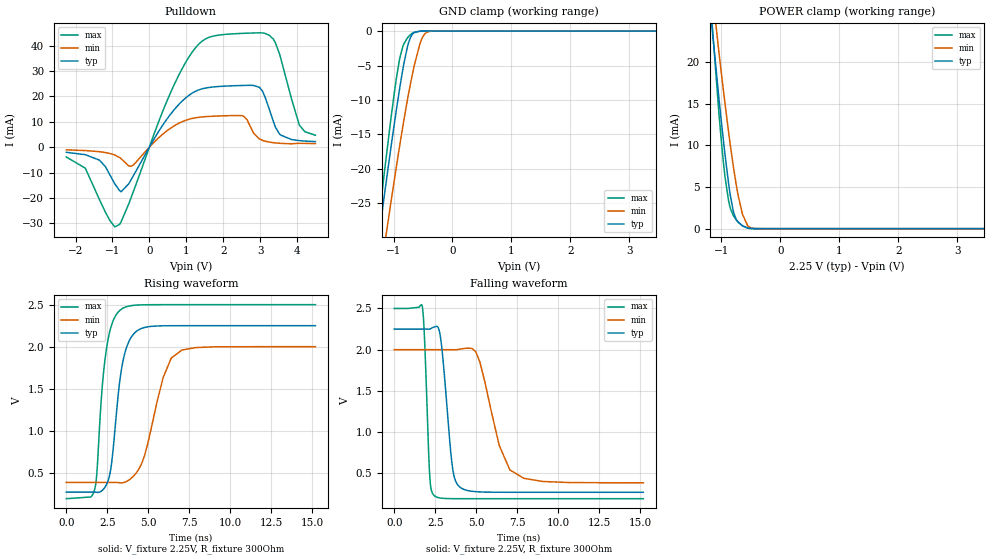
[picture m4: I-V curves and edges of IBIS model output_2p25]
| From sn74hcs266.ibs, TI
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|   output_2p25 Model
[Model]   output_2p25
Model_type   Output
Polarity   Non-Inverting
Vmeas = 1.125
Vref = 0
Cref = 2pF
Rref = 100000
|   typ   min   max
C_comp   0.937pF   0.886pF   0.963pF
| Where Nom  PVT is Nominal Process, 2.25V, 27C
|   Fast PVT is Strong Process,  2.50V, -55C
|   Slow PVT is Weak Process,   2.0V, 150C
[Voltage Range]   2.25   2   2.5
|Junction Temperature
[Temperature Range]   27   150   -55
[Pulldown Reference]   0   0   0
[Power Clamp Reference]   2.25   2   2.5
[GND Clamp Reference]   0   0   0
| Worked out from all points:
|   slope of the pulldown table from 0 to 0.337 V, typ, clamps not added: 41.6 ohm
|   GND clamp passes 1 mA (typ) near -0.72 V on its own axis
|   POWER clamp passes 1 mA (typ) near -0.74 V on its own axis
|   falling waveform, V_fixture 2.25V, R_fixture 300Ohm: 20-80 % time 508ps typ, 1.25ns min, 251ps max; typ from 2.25 V to 0.269 V
|   rising waveform, V_fixture 2.25V, R_fixture 300Ohm: 20-80 % time 690ps typ, 1.22ns min, 587ps max; typ from 0.269 V to 2.25 V
[Pulldown]
|   Voltage   I(typ)   I(min)   I(max)
-2.25V    -2.019mA   -1.051mA   -3.867mA
-1.737V   -2.956mA   -1.338mA   -8.261mA
-1.352V   -5.109mA   -1.777mA   -20.65mA
-805.5mV  -17.13mA   -4.093mA   -30.48mA
-461.2mV  -11.99mA   -7.313mA   -18.63mA
949.5mV   18.99mA    10.42mA    32.57mA
2.057V    24.09mA    12.39mA    44.49mA
2.556V    24.35mA    12.19mA    44.91mA
2.981V    23.61mA    3.258mA    45.1mA
3.359V    10.14mA    1.771mA    42.63mA
4.061V    2.596mA    1.53mA     8.818mA
4.5V      2.197mA    1.398mA    4.702mA
[GND Clamp]
|   Voltage   I(typ)   I(min)   I(max)
-2.25V    -97.51mA   -98.31mA   -106.7mA
-1.413V   -40.56mA   -46.57mA   -39.9mA
-1.17V    -24.74mA   -32.11mA   -21.56mA
-1.157V   -23.88mA   -31.32mA   -20.58mA
-1.048V   -17.16mA   -25.09mA   -13.01mA
-954mV    -11.56mA   -19.8mA    -7.02mA
-886.5mV  -7.821mA   -16.15mA   -3.647mA
-758.2mV  -2.094mA   -9.706mA   -933.8uA
-650.2mV  -236.3uA   -5.079mA   -178.5uA
-515.2mV  -9.553uA   -1.047mA   -5.579uA
-373.5mV  -159.7nA   -38.68uA   -18.72nA
4.5V      0A         0A         0A
[POWER Clamp]
|   Voltage   I(typ)   I(min)   I(max)
-2.25V    111.3mA    101.8mA    143.6mA
-1.305V   34.66mA    37.92mA    38.3mA
-1.042V   15.57mA    21.11mA    13.76mA
-987.8mV  11.94mA    17.84mA    9.441mA
-940.5mV  8.946mA    15.06mA    6.255mA
-879.8mV  5.467mA    11.64mA    3.383mA
-792mV    1.914mA    7.17mA     1.486mA
-717.7mV  771.2uA    4.03mA     811.5uA
-643.5mV  332.5uA    1.729mA    341.9uA
-555.7mV  82.38uA    359.8uA    63.02uA
-420.8mV  3.273uA    16.09uA    933.6nA
4.5V      0A         0A         0A
[Ramp]
R_load = 300
|   typ   min   max
dV/dt_r   1.35/810e-12   1.2/1.923e-9   1.5/613e-12
dV/dt_f   1.35/656e-12   1.2/2.74e-9   1.5/301.4e-12
[Falling Waveform]
V_fixture = 2.25V
V_fixture_min = 2V
V_fixture_max = 2.5V
R_fixture = 300Ohm
C_fixture = 0F
|   Time   V(typ)   V(min)   V(max)
0s        2.25V      2V         2.5V
1.706ns   2.25V      2V         2.531V
2.161ns   2.25V      2V         482.9mV
2.438ns   2.276V     2V         229mV
2.826ns   2.144V     2V         198.9mV
3.514ns   631.3mV    2V         191.9mV
3.978ns   335.9mV    2.005V     191.5mV
4.976ns   276.4mV    1.973V     191.4mV
7.047ns   269.4mV    542mV      191.4mV
15.19ns   269.3mV    384.5mV    191.4mV
[Rising Waveform]
V_fixture = 2.25V
V_fixture_min = 2V
V_fixture_max = 2.5V
R_fixture = 300Ohm
C_fixture = 0F
|   Time   V(typ)   V(min)   V(max)
0s        269.3mV    384.5mV    191.4mV
1.715ns   269.5mV    384.5mV    291.3mV
2.438ns   353.1mV    384.5mV    1.96V
2.778ns   635.6mV    384.7mV    2.267V
3.278ns   1.616V     380.4mV    2.434V
4.252ns   2.179V     494.7mV    2.494V
4.764ns   2.228V     700.1mV    2.498V
5.907ns   2.248V     1.635V     2.5V
7.047ns   2.25V      1.96V      2.5V
15.19ns   2.25V      2V         2.5V
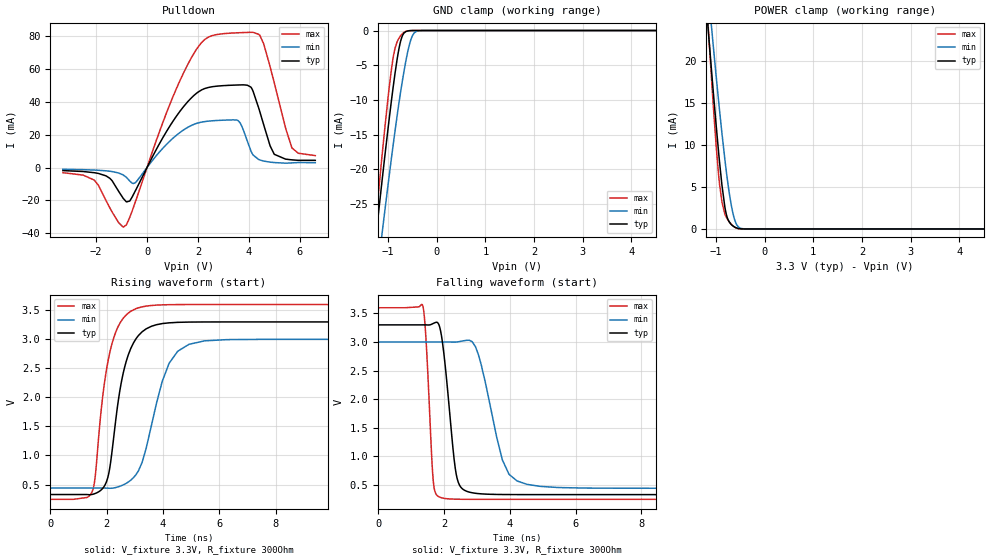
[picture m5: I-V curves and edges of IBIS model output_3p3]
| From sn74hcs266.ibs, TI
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|   output_3p3 Model
[Model]   output_3p3
Model_type   Output
Polarity   Non-Inverting
Vmeas = 1.65
Vref = 0
Cref = 2pF
Rref = 100000
|   typ   min   max
C_comp   0.878pF   0.839pF   0.891pF
| Where Nom  PVT is Nominal Process, 3.3V, 27C
|   Fast PVT is Strong Process,  3.6V, -55C
|   Slow PVT is Weak Process,   3.0V, 150C
[Voltage Range]   3.3   3   3.6
|Junction Temperature
[Temperature Range]   27   150   -55
[Pulldown Reference]   0   0   0
[Power Clamp Reference]   3.3   3   3.6
[GND Clamp Reference]   0   0   0
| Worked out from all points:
|   slope of the pulldown table from 0 to 0.495 V, typ, clamps not added: 33.8 ohm
|   GND clamp passes 1 mA (typ) near -0.72 V on its own axis
|   POWER clamp passes 1 mA (typ) near -0.74 V on its own axis
|   falling waveform, V_fixture 3.3V, R_fixture 300Ohm: 20-80 % time 299ps typ, 590ps min, 168ps max; typ from 3.3 V to 0.328 V
|   rising waveform, V_fixture 3.3V, R_fixture 300Ohm: 20-80 % time 599ps typ, 838ps min, 545ps max; typ from 0.328 V to 3.3 V
[Pulldown]
|   Voltage   I(typ)   I(min)   I(max)
-3.3V     -1.874mA   -1.09mA    -3.153mA
-2.072V   -3.148mA   -1.553mA   -7.616mA
-815.1mV  -20.76mA   -5.906mA   -34.91mA
-468.6mV  -14.47mA   -9.363mA   -21.34mA
1.719V    41.96mA    25.37mA    66.07mA
3.244V    49.91mA    28.86mA    81.54mA
3.66V     50.14mA    26.88mA    81.86mA
4.075V    48.79mA    10.04mA    82.07mA
4.422V    33.99mA    4.608mA    80.33mA
4.986V    8.151mA    3.011mA    51.62mA
5.679V    4.642mA    2.795mA    12.07mA
6.6V      4.33mA     2.888mA    7.224mA
[GND Clamp]
|   Voltage   I(typ)   I(min)   I(max)
-3.3V     -170.7mA   -164.8mA   -192.4mA
-1.27V    -31.2mA    -38.03mA   -29.01mA
-1.122V   -21.71mA   -29.31mA   -18.11mA
-1.073V   -18.63mA   -26.46mA   -14.64mA
-983.4mV  -13.27mA   -21.43mA   -8.78mA
-894.3mV  -8.237mA   -16.57mA   -3.969mA
-815.1mV  -4.303mA   -12.46mA   -1.69mA
-755.7mV  -2.013mA   -9.587mA   -907.2uA
-636.9mV  -174.3uA   -4.574mA   -135.1uA
-498.3mV  -6.151uA   -766.4uA   -3.251uA
-339.9mV  -43.96nA   -15.79uA   0A
6.6V      0A         0A         0A
[POWER Clamp]
|   Voltage   I(typ)   I(min)   I(max)
-3.3V     211.7mA    184.7mA    283.2mA
-1.152V   23.34mA    28mA       23.6mA
-1.073V   17.7mA     23.01mA    16.41mA
-993.3mV  12.31mA    18.17mA    9.859mA
-943.8mV  9.149mA    15.25mA    6.453mA
-874.5mV  5.196mA    11.36mA    3.199mA
-815.1mV  2.61mA     8.282mA    1.781mA
-765.6mV  1.349mA    5.972mA    1.216mA
-666.6mV  440uA      2.342mA    466.4uA
-577.5mV  123.3uA    563.4uA    104.5uA
-290.4mV  398.2nA    738.5nA    0A
6.6V      0A         0A         0A
[Ramp]
R_load = 300
|   typ   min   max
dV/dt_r   1.98/645e-12   1.8/1.04e-9   2.16/559e-12
dV/dt_f   1.98/353e-12   1.8/816e-12   2.16/196.5e-12
[Falling Waveform]
V_fixture = 3.3V
V_fixture_min = 3V
V_fixture_max = 3.6V
R_fixture = 300Ohm
C_fixture = 0F
|   Time   V(typ)   V(min)   V(max)
0s        3.3V       3V         3.6V
1.357ns   3.3V       3V         3.63V
1.672ns   3.325V     3V         576.9mV
1.897ns   3.194V     3V         277mV
2.344ns   783.3mV    2.999V     247.9mV
2.696ns   384.6mV    3.03V      245.5mV
3.048ns   345mV      2.775V     245.1mV
3.774ns   329.4mV    935.7mV    245mV
4.219ns   328mV      567.2mV    245mV
15.48ns   327.5mV    438.8mV    245mV
[Rising Waveform]
V_fixture = 3.3V
V_fixture_min = 3V
V_fixture_max = 3.6V
R_fixture = 300Ohm
C_fixture = 0F
|   Time   V(typ)   V(min)   V(max)
0s        327.5mV    438.8mV    245mV
1.475ns   328.2mV    438.8mV    365.8mV
1.594ns   345.3mV    438.8mV    627.8mV
1.945ns   493.5mV    438.9mV    2.319V
2.114ns   789.2mV    435.4mV    2.772V
2.55ns    2.327V     485.3mV    3.336V
3.048ns   3.013V     672.2mV    3.529V
4.219ns   3.284V     2.587V     3.597V
4.93ns    3.297V     2.915V     3.599V
15.48ns   3.3V       3V         3.6V
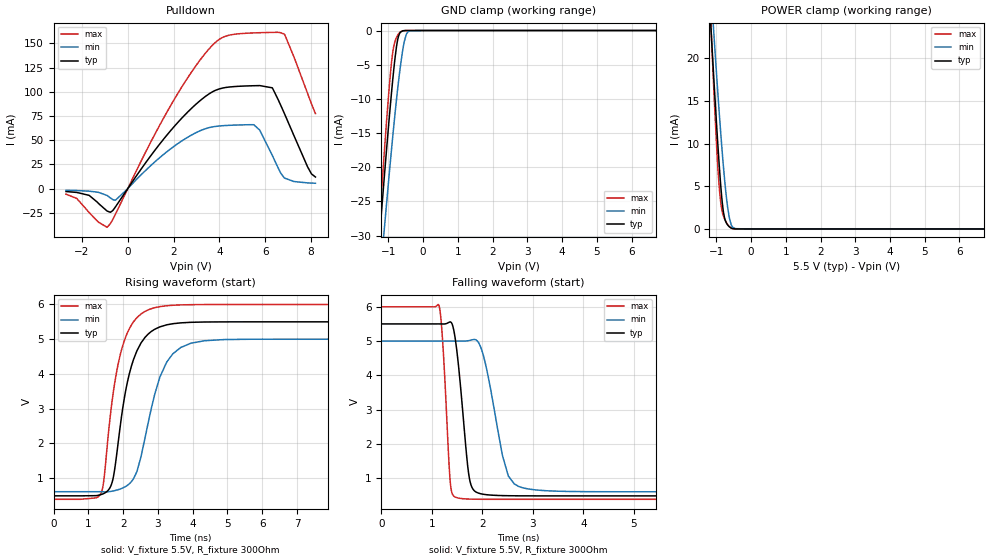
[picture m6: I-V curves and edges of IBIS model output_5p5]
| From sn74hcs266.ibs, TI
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|   output_5p5 Model
[Model]   output_5p5
Model_type   Output
Polarity   Non-Inverting
Vmeas = 2.75
Vref = 0
Cref = 2pF
Rref = 100000
|   typ   min   max
C_comp   0.801pF   0.769pF   0.801pF
| Where Nom  PVT is Nominal Process, 5.5V, 27C
|   Fast PVT is Strong Process,  6.0V, -55C
|   Slow PVT is Weak Process,   5.0V, 150C
[Voltage Range]   5.5   5   6
|Junction Temperature
[Temperature Range]   27   150   -55
[Pulldown Reference]   0   0   0
[Power Clamp Reference]   5.5   5   6
[GND Clamp Reference]   0   0   0
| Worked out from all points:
|   slope of the pulldown table from 0 to 0.825 V, typ, clamps not added: 29.3 ohm
|   GND clamp passes 1 mA (typ) near -0.72 V on its own axis
|   POWER clamp passes 1 mA (typ) near -0.74 V on its own axis
|   falling waveform, V_fixture 5.5V, R_fixture 300Ohm: 20-80 % time 189ps typ, 339ps min, 118ps max; typ from 5.5 V to 0.481 V
|   rising waveform, V_fixture 5.5V, R_fixture 300Ohm: 20-80 % time 540ps typ, 675ps min, 504ps max; typ from 0.481 V to 5.5 V
[Pulldown]
|   Voltage   I(typ)   I(min)   I(max)
-2.7V     -3.055mA   -1.706mA   -5.778mA
-1.686V   -7.04mA    -2.68mA    -24.81mA
-901.5mV  -23.23mA   -7.206mA   -39.81mA
-541.8mV  -18.99mA   -12.08mA   -26.61mA
2.325V    71.94mA    48.73mA    103.7mA
3.546V    97.82mA    62.97mA    144.3mA
4.309V    104.6mA    65.26mA    157.8mA
5.508V    106.3mA    65.99mA    160.9mA
6.314V    104.2mA    34.33mA    161.5mA
6.827V    78.5mA     11.4mA     159.8mA
7.862V    22.23mA    5.883mA    97.97mA
8.2V      11.95mA    5.526mA    77.53mA
[GND Clamp]
|   Voltage   I(typ)   I(min)   I(max)
-2.7V     -128.8mA   -126.7mA   -143.3mA
-1.37V    -37.73mA   -43.99mA   -36.6mA
-1.25V    -29.89mA   -36.83mA   -27.5mA
-1.119V   -21.55mA   -29.17mA   -17.93mA
-988.7mV  -13.58mA   -21.72mA   -9.11mA
-901.5mV  -8.626mA   -16.95mA   -4.285mA
-836.1mV  -5.272mA   -13.52mA   -2.102mA
-759.8mV  -2.144mA   -9.779mA   -950.2uA
-650.8mV  -239.3uA   -5.101mA   -180.5uA
-541.8mV  -18.61uA   -1.605mA   -12.31uA
-378.3mV  -181.5nA   -43.9uA    -26.91nA
8.2V      0A         0A         0A
[POWER Clamp]
|   Voltage   I(typ)   I(min)   I(max)
-2.7V     153.5mA    137.3mA    203.1mA
-1.207V   27.35mA    31.53mA    28.8mA
-1.098V   19.47mA    24.59mA    18.65mA
-1.054V   16.42mA    21.87mA    14.81mA
-966.9mV  10.6mA     16.6mA     7.948mA
-879.7mV  5.467mA    11.64mA    3.382mA
-814.3mV  2.584mA    8.244mA    1.77mA
-759.8mV  1.253mA    5.722mA    1.163mA
-672.6mV  471.3uA    2.518mA    502uA
-574.5mV  116.9uA    531.2uA    97.83uA
-29.5mV   0A         0A         0A
8.2V      0A         0A         0A
[Ramp]
R_load = 300
|   typ   min   max
dV/dt_r   3.3/560e-12   3/729e-12   3.6/513e-12
dV/dt_f   3.3/212.6e-12   3/392e-12   3.6/134e-12
[Falling Waveform]
V_fixture = 5.5V
V_fixture_min = 5V
V_fixture_max = 6V
R_fixture = 300Ohm
C_fixture = 0F
|   Time   V(typ)   V(min)   V(max)
0s        5.5V       5V         6V
1.136ns   5.5V       5V         6.052V
1.216ns   5.498V     5V         4.922V
1.367ns   5.559V     5V         823.6mV
1.52ns    4.37V      5V         418.5mV
1.793ns   730.3mV    5.034V     385.8mV
2.018ns   528.6mV    4.586V     381.7mV
2.514ns   486.1mV    1.06V      380.6mV
2.905ns   482mV      683.9mV    380.5mV
15.46ns   481mV      600.3mV    380.5mV
[Rising Waveform]
V_fixture = 5.5V
V_fixture_min = 5V
V_fixture_max = 6V
R_fixture = 300Ohm
C_fixture = 0F
|   Time   V(typ)   V(min)   V(max)
0s        480.9mV    600.3mV    380.5mV
1.34ns    510.4mV    601mV      516.4mV
1.446ns   548.9mV    597.1mV    928mV
1.615ns   704.1mV    605.1mV    2.641V
2.054ns   3.405V     740.3mV    5.008V
2.396ns   4.662V     1.179V     5.62V
2.805ns   5.218V     2.977V     5.877V
3.43ns    5.446V     4.578V     5.978V
4.333ns   5.495V     4.954V     5.998V
15.46ns   5.5V       5V         6V
